VERSION 5.7 ;
  NOWIREEXTENSIONATPIN ON ;
  DIVIDERCHAR "/" ;
  BUSBITCHARS "[]" ;
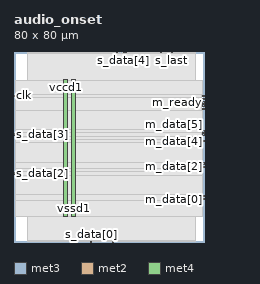
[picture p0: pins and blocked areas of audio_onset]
MACRO audio_onset
  CLASS BLOCK ;
  FOREIGN audio_onset ;
  ORIGIN 0.000 0.000 ;
  SIZE 80.000 BY 80.000 ;
  PIN clk
    DIRECTION INPUT ;
    USE SIGNAL ;
    ANTENNAGATEAREA 1.286700 ;
    ANTENNADIFFAREA 0.434700 ;
    PORT
      LAYER met3 ;
        RECT 0.000 61.240 0.600 61.840 ;
    END
  END clk
  PIN m_data[0]
    DIRECTION OUTPUT ;
    USE SIGNAL ;
    ANTENNADIFFAREA 0.795200 ;
    PORT
      LAYER met3 ;
        RECT 79.400 17.720 80.000 18.320 ;
    END
  END m_data[0]
  PIN m_data[1]
    DIRECTION OUTPUT ;
    USE SIGNAL ;
    ANTENNADIFFAREA 0.795200 ;
    PORT
      LAYER met3 ;
        RECT 79.400 19.080 80.000 19.680 ;
    END
  END m_data[1]
  PIN m_data[2]
    DIRECTION OUTPUT ;
    USE SIGNAL ;
    ANTENNADIFFAREA 0.795200 ;
    PORT
      LAYER met3 ;
        RECT 79.400 31.320 80.000 31.920 ;
    END
  END m_data[2]
  PIN m_data[3]
    DIRECTION OUTPUT ;
    USE SIGNAL ;
    ANTENNADIFFAREA 0.795200 ;
    PORT
      LAYER met3 ;
        RECT 79.400 32.680 80.000 33.280 ;
    END
  END m_data[3]
  PIN m_data[4]
    DIRECTION OUTPUT ;
    USE SIGNAL ;
    ANTENNADIFFAREA 0.795200 ;
    PORT
      LAYER met3 ;
        RECT 79.400 42.200 80.000 42.800 ;
    END
  END m_data[4]
  PIN m_data[5]
    DIRECTION OUTPUT ;
    USE SIGNAL ;
    ANTENNADIFFAREA 0.795200 ;
    PORT
      LAYER met3 ;
        RECT 79.400 46.280 80.000 46.880 ;
    END
  END m_data[5]
  PIN m_data[6]
    DIRECTION OUTPUT ;
    USE SIGNAL ;
    ANTENNADIFFAREA 0.795200 ;
    PORT
      LAYER met3 ;
        RECT 79.400 44.920 80.000 45.520 ;
    END
  END m_data[6]
  PIN m_data[7]
    DIRECTION OUTPUT ;
    USE SIGNAL ;
    ANTENNADIFFAREA 0.795200 ;
    PORT
      LAYER met2 ;
        RECT 47.010 79.720 47.290 80.000 ;
    END
  END m_data[7]
  PIN m_last
    DIRECTION OUTPUT ;
    USE SIGNAL ;
    ANTENNADIFFAREA 0.795200 ;
    PORT
      LAYER met3 ;
        RECT 79.400 61.240 80.000 61.840 ;
    END
  END m_last
  PIN m_ready
    DIRECTION INPUT ;
    USE SIGNAL ;
    ANTENNAGATEAREA 0.647700 ;
    ANTENNADIFFAREA 0.434700 ;
    PORT
      LAYER met3 ;
        RECT 79.400 58.520 80.000 59.120 ;
    END
  END m_ready
  PIN m_valid
    DIRECTION OUTPUT ;
    USE SIGNAL ;
    ANTENNADIFFAREA 0.795200 ;
    PORT
      LAYER met3 ;
        RECT 79.400 59.880 80.000 60.480 ;
    END
  END m_valid
  PIN rst
    DIRECTION INPUT ;
    USE SIGNAL ;
    ANTENNAGATEAREA 0.631200 ;
    ANTENNADIFFAREA 0.434700 ;
    PORT
      LAYER met2 ;
        RECT 61.730 79.720 62.010 80.000 ;
    END
  END rst
  PIN s_data[0]
    DIRECTION INPUT ;
    USE SIGNAL ;
    ANTENNAGATEAREA 0.647700 ;
    ANTENNADIFFAREA 0.434700 ;
    PORT
      LAYER met2 ;
        RECT 32.290 0.000 32.570 0.280 ;
    END
  END s_data[0]
  PIN s_data[1]
    DIRECTION INPUT ;
    USE SIGNAL ;
    ANTENNAGATEAREA 0.647700 ;
    ANTENNADIFFAREA 0.434700 ;
    PORT
      LAYER met2 ;
        RECT 41.490 0.000 41.770 0.280 ;
    END
  END s_data[1]
  PIN s_data[2]
    DIRECTION INPUT ;
    USE SIGNAL ;
    ANTENNAGATEAREA 0.647700 ;
    ANTENNADIFFAREA 0.434700 ;
    PORT
      LAYER met3 ;
        RECT 0.000 28.600 0.600 29.200 ;
    END
  END s_data[2]
  PIN s_data[3]
    DIRECTION INPUT ;
    USE SIGNAL ;
    ANTENNAGATEAREA 0.647700 ;
    ANTENNADIFFAREA 0.434700 ;
    PORT
      LAYER met3 ;
        RECT 0.000 44.920 0.600 45.520 ;
    END
  END s_data[3]
  PIN s_data[4]
    DIRECTION INPUT ;
    USE SIGNAL ;
    ANTENNAGATEAREA 0.647700 ;
    ANTENNADIFFAREA 0.434700 ;
    PORT
      LAYER met2 ;
        RECT 46.090 79.720 46.370 80.000 ;
    END
  END s_data[4]
  PIN s_data[5]
    DIRECTION INPUT ;
    USE SIGNAL ;
    ANTENNAGATEAREA 0.647700 ;
    ANTENNADIFFAREA 0.434700 ;
    PORT
      LAYER met2 ;
        RECT 44.250 79.720 44.530 80.000 ;
    END
  END s_data[5]
  PIN s_data[6]
    DIRECTION INPUT ;
    USE SIGNAL ;
    ANTENNAGATEAREA 0.647700 ;
    ANTENNADIFFAREA 0.434700 ;
    PORT
      LAYER met2 ;
        RECT 45.170 79.720 45.450 80.000 ;
    END
  END s_data[6]
  PIN s_data[7]
    DIRECTION INPUT ;
    USE SIGNAL ;
    ANTENNAGATEAREA 0.647700 ;
    ANTENNADIFFAREA 0.434700 ;
    PORT
      LAYER met2 ;
        RECT 43.330 79.720 43.610 80.000 ;
    END
  END s_data[7]
  PIN s_last
    DIRECTION INPUT ;
    USE SIGNAL ;
    ANTENNAGATEAREA 0.647700 ;
    ANTENNADIFFAREA 0.434700 ;
    PORT
      LAYER met2 ;
        RECT 66.330 79.720 66.610 80.000 ;
    END
  END s_last
  PIN s_ready
    DIRECTION OUTPUT ;
    USE SIGNAL ;
    ANTENNADIFFAREA 0.795200 ;
    PORT
      LAYER met3 ;
        RECT 79.400 57.160 80.000 57.760 ;
    END
  END s_ready
  PIN s_valid
    DIRECTION INPUT ;
    USE SIGNAL ;
    ANTENNAGATEAREA 0.647700 ;
    ANTENNADIFFAREA 0.434700 ;
    PORT
      LAYER met3 ;
        RECT 79.400 55.800 80.000 56.400 ;
    END
  END s_valid
  PIN vccd1
    DIRECTION INOUT ;
    USE POWER ;
    PORT
      LAYER met4 ;
        RECT 21.040 10.640 22.640 68.240 ;
    END
  END vccd1
  PIN vssd1
    DIRECTION INOUT ;
    USE GROUND ;
    PORT
      LAYER met4 ;
        RECT 24.340 10.640 25.940 68.240 ;
    END
  END vssd1
  OBS
      LAYER nwell ;
        RECT 5.330 10.795 74.250 68.190 ;
      LAYER li1 ;
        RECT 5.520 10.795 74.060 68.085 ;
      LAYER met1 ;
        RECT 5.520 10.640 76.290 68.240 ;
      LAYER met2 ;
        RECT 5.610 79.440 43.050 79.720 ;
        RECT 43.890 79.440 43.970 79.720 ;
        RECT 44.810 79.440 44.890 79.720 ;
        RECT 45.730 79.440 45.810 79.720 ;
        RECT 46.650 79.440 46.730 79.720 ;
        RECT 47.570 79.440 61.450 79.720 ;
        RECT 62.290 79.440 66.050 79.720 ;
        RECT 66.890 79.440 76.270 79.720 ;
        RECT 5.610 0.560 76.270 79.440 ;
        RECT 5.610 0.280 32.010 0.560 ;
        RECT 32.850 0.280 41.210 0.560 ;
        RECT 42.050 0.280 76.270 0.560 ;
      LAYER met3 ;
        RECT 0.600 62.240 79.400 68.165 ;
        RECT 1.000 60.840 79.000 62.240 ;
        RECT 0.600 55.400 79.000 60.840 ;
        RECT 0.600 47.280 79.400 55.400 ;
        RECT 0.600 45.920 79.000 47.280 ;
        RECT 1.000 44.520 79.000 45.920 ;
        RECT 0.600 43.200 79.400 44.520 ;
        RECT 0.600 41.800 79.000 43.200 ;
        RECT 0.600 33.680 79.400 41.800 ;
        RECT 0.600 30.920 79.000 33.680 ;
        RECT 0.600 29.600 79.400 30.920 ;
        RECT 1.000 28.200 79.400 29.600 ;
        RECT 0.600 20.080 79.400 28.200 ;
        RECT 0.600 17.320 79.000 20.080 ;
        RECT 0.600 10.715 79.400 17.320 ;
  END
END audio_onset
END LIBRARY

